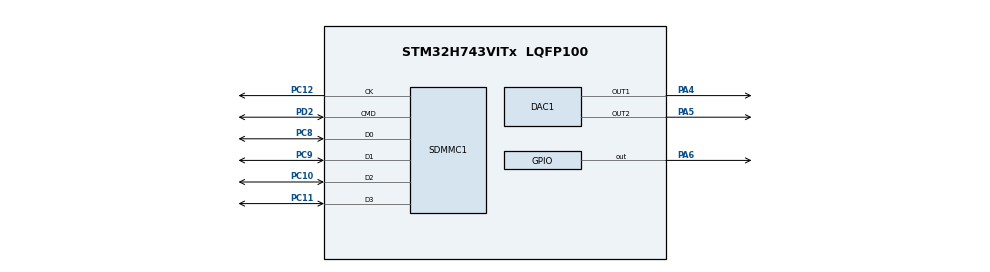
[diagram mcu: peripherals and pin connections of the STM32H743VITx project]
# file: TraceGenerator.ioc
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DAC1.DAC_Channel-DAC_OUT2=DAC_CHANNEL_2
Mcu.Family=STM32H7
Mcu.Name=STM32H743VITx
Mcu.Package=LQFP100
NVIC.PriorityGroup=NVIC_PRIORITYGROUP_4
PA13\ (JTMS/SWDIO).Mode=Serial_Wire
PA13\ (JTMS/SWDIO).Signal=DEBUG_JTMS-SWDIO
PA14\ (JTCK/SWCLK).Mode=Serial_Wire
PA14\ (JTCK/SWCLK).Signal=DEBUG_JTCK-SWCLK
PA4.Signal=COMP_DAC11_group
PA5.Signal=COMP_DAC12_group
PA6.Signal=GPIO_Output
PC10.Mode=SD_4_bits_Wide_bus
PC10.Signal=SDMMC1_D2
PC11.Mode=SD_4_bits_Wide_bus
PC11.Signal=SDMMC1_D3
PC12.Mode=SD_4_bits_Wide_bus
PC12.Signal=SDMMC1_CK
PC8.Mode=SD_4_bits_Wide_bus
PC8.Signal=SDMMC1_D0
PC9.Mode=SD_4_bits_Wide_bus
PC9.Signal=SDMMC1_D1
PD2.Mode=SD_4_bits_Wide_bus
PD2.Signal=SDMMC1_CMD
ProjectManager.HeapSize=0x200
ProjectManager.StackSize=0x400
ProjectManager.TargetToolchain=STM32CubeIDE
RCC.ADCFreq_Value=129000000
RCC.APB1Freq_Value=95600000
RCC.APB2Freq_Value=95600000
RCC.APB3Freq_Value=95600000
RCC.APB4Freq_Value=95600000
RCC.CortexFreq_Value=95600000
RCC.DIVN1=478
RCC.DIVP1=10
RCC.HCLKFreq_Value=95600000
RCC.SYSCLKFreq_VALUE=95600000
RCC.SYSCLKSource=RCC_SYSCLKSOURCE_PLLCLK
RCC.USBFreq_Value=478000000
SH.COMP_DAC11_group.0=DAC1_OUT1,DAC_OUT1
SH.COMP_DAC12_group.0=DAC1_OUT2,DAC_OUT2
VP_FATFS_VS_SDIO.Mode=SDIO
board=custom

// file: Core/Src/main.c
/* USER CODE BEGIN Header */
/**
  ******************************************************************************
  * @file           : main.c
  * @brief          : Main program body
  ******************************************************************************
  * @attention
  *
  * <h2><center>&copy; Copyright (c) 2020 STMicroelectronics.
  * All rights reserved.</center></h2>
  *
  * This software component is licensed by ST under BSD 3-Clause license,
  * the "License"; You may not use this file except in compliance with the
  * License. You may obtain a copy of the License at:
  *                        opensource.org/licenses/BSD-3-Clause
  *
  ******************************************************************************
  */
/* USER CODE END Header */
#include "main.h"
#include "fatfs.h"

DAC_HandleTypeDef hdac1;

SD_HandleTypeDef hsd1;

void SystemClock_Config(void);
static void MX_GPIO_Init(void);
static void MX_DAC1_Init(void);
static void MX_SDMMC1_SD_Init(void);

int main(void)
{

  /* MCU Configuration--------------------------------------------------------*/

  /* Reset of all peripherals, Initializes the Flash interface and the Systick. */
  HAL_Init();

  /* Configure the system clock */
  SystemClock_Config();

  /* Initialize all configured peripherals */
  MX_GPIO_Init();
  MX_DAC1_Init();
  MX_SDMMC1_SD_Init();
  MX_FATFS_Init();
  /* USER CODE BEGIN 2 */
  HAL_DAC_Start(&hdac1, DAC1_CHANNEL_1);
  HAL_DAC_Start(&hdac1, DAC1_CHANNEL_2);
  double x = 0.0;
  double x1 = 0.0;
  uint16_t y[2000];
  uint16_t y_[2000];

  for(int i=0; i < 2000; i++)
  {
	  int j = i - 500;
  	  x = (j*j*0.00002 + log(j+3));
  	  x1 = exp(-fabs(j*0.01-3));
  	  y[i]= (uint16_t)((sin(pow(x*0.5, 2) + 3)+1)*3000.0*x1);
  }
  for(int i=0; i < 2000; i++)
    {
  	  int j = i - 700;
    	  x = (j*j*0.00002 + log(j+3));
    	  x1 = exp(-fabs(j*0.01-3));
    	  y_[i]= (uint16_t)((sin(pow(x*0.5, 2) + 3)+1)*2000.0*x1);
    }
  for(int i = 20; i < 50; i++) {
	  y[i] = 4000;
  }
  /* USER CODE END 2 */

  /* Infinite loop */
  /* USER CODE BEGIN WHILE */
  while (1)
  {
	  HAL_GPIO_TogglePin(GPIOA, GPIO_PIN_6);
	  for(int i =0; i<100; i++){}
	  HAL_GPIO_TogglePin(GPIOA, GPIO_PIN_6);
	  for(int i=0; i < 2000; i++)
	  {
	  	  HAL_DAC_SetValue(&hdac1, DAC1_CHANNEL_1, DAC_ALIGN_12B_R, y_[i]);
	  	  HAL_DAC_SetValue(&hdac1, DAC1_CHANNEL_2, DAC_ALIGN_12B_R, y[i]);
	  }
    /* USER CODE END WHILE */

  }
}

void SystemClock_Config(void)
{
  RCC_OscInitTypeDef RCC_OscInitStruct = {0};
  RCC_ClkInitTypeDef RCC_ClkInitStruct = {0};
  RCC_PeriphCLKInitTypeDef PeriphClkInitStruct = {0};

  /** Supply configuration update enable
  */
  HAL_PWREx_ConfigSupply(PWR_LDO_SUPPLY);
  /** Configure the main internal regulator output voltage
  */
  __HAL_PWR_VOLTAGESCALING_CONFIG(PWR_REGULATOR_VOLTAGE_SCALE3);

  while(!__HAL_PWR_GET_FLAG(PWR_FLAG_VOSRDY)) {}
  /** Initializes the RCC Oscillators according to the specified parameters
  * in the RCC_OscInitTypeDef structure.
  */
  RCC_OscInitStruct.OscillatorType = RCC_OSCILLATORTYPE_HSI;
  RCC_OscInitStruct.HSIState = RCC_HSI_DIV1;
  RCC_OscInitStruct.HSICalibrationValue = RCC_HSICALIBRATION_DEFAULT;
  RCC_OscInitStruct.PLL.PLLState = RCC_PLL_ON;
  RCC_OscInitStruct.PLL.PLLSource = RCC_PLLSOURCE_HSI;
  RCC_OscInitStruct.PLL.PLLM = 32;
  RCC_OscInitStruct.PLL.PLLN = 129;
  RCC_OscInitStruct.PLL.PLLP = 2;
  RCC_OscInitStruct.PLL.PLLQ = 2;
  RCC_OscInitStruct.PLL.PLLR = 2;
  RCC_OscInitStruct.PLL.PLLRGE = RCC_PLL1VCIRANGE_1;
  RCC_OscInitStruct.PLL.PLLVCOSEL = RCC_PLL1VCOWIDE;
  RCC_OscInitStruct.PLL.PLLFRACN = 0;
  if (HAL_RCC_OscConfig(&RCC_OscInitStruct) != HAL_OK)
  {
    Error_Handler();
  }
  /** Initializes the CPU, AHB and APB buses clocks
  */
  RCC_ClkInitStruct.ClockType = RCC_CLOCKTYPE_HCLK|RCC_CLOCKTYPE_SYSCLK
                              |RCC_CLOCKTYPE_PCLK1|RCC_CLOCKTYPE_PCLK2
                              |RCC_CLOCKTYPE_D3PCLK1|RCC_CLOCKTYPE_D1PCLK1;
  RCC_ClkInitStruct.SYSCLKSource = RCC_SYSCLKSOURCE_HSI;
  RCC_ClkInitStruct.SYSCLKDivider = RCC_SYSCLK_DIV1;
  RCC_ClkInitStruct.AHBCLKDivider = RCC_HCLK_DIV1;
  RCC_ClkInitStruct.APB3CLKDivider = RCC_APB3_DIV1;
  RCC_ClkInitStruct.APB1CLKDivider = RCC_APB1_DIV1;
  RCC_ClkInitStruct.APB2CLKDivider = RCC_APB2_DIV1;
  RCC_ClkInitStruct.APB4CLKDivider = RCC_APB4_DIV1;

  if (HAL_RCC_ClockConfig(&RCC_ClkInitStruct, FLASH_LATENCY_0) != HAL_OK)
  {
    Error_Handler();
  }
  PeriphClkInitStruct.PeriphClockSelection = RCC_PERIPHCLK_SDMMC;
  PeriphClkInitStruct.SdmmcClockSelection = RCC_SDMMCCLKSOURCE_PLL;
  if (HAL_RCCEx_PeriphCLKConfig(&PeriphClkInitStruct) != HAL_OK)
  {
    Error_Handler();
  }
}

static void MX_DAC1_Init(void)
{

  DAC_ChannelConfTypeDef sConfig = {0};

  /** DAC Initialization
  */
  hdac1.Instance = DAC1;
  if (HAL_DAC_Init(&hdac1) != HAL_OK)
  {
    Error_Handler();
  }
  /** DAC channel OUT1 config
  */
  sConfig.DAC_SampleAndHold = DAC_SAMPLEANDHOLD_DISABLE;
  sConfig.DAC_Trigger = DAC_TRIGGER_NONE;
  sConfig.DAC_OutputBuffer = DAC_OUTPUTBUFFER_ENABLE;
  sConfig.DAC_ConnectOnChipPeripheral = DAC_CHIPCONNECT_DISABLE;
  sConfig.DAC_UserTrimming = DAC_TRIMMING_FACTORY;
  if (HAL_DAC_ConfigChannel(&hdac1, &sConfig, DAC_CHANNEL_1) != HAL_OK)
  {
    Error_Handler();
  }
  /** DAC channel OUT2 config
  */
  sConfig.DAC_ConnectOnChipPeripheral = DAC_CHIPCONNECT_DISABLE;
  if (HAL_DAC_ConfigChannel(&hdac1, &sConfig, DAC_CHANNEL_2) != HAL_OK)
  {
    Error_Handler();
  }

}

static void MX_SDMMC1_SD_Init(void)
{

  hsd1.Instance = SDMMC1;
  hsd1.Init.ClockEdge = SDMMC_CLOCK_EDGE_RISING;
  hsd1.Init.ClockPowerSave = SDMMC_CLOCK_POWER_SAVE_DISABLE;
  hsd1.Init.BusWide = SDMMC_BUS_WIDE_4B;
  hsd1.Init.HardwareFlowControl = SDMMC_HARDWARE_FLOW_CONTROL_DISABLE;
  hsd1.Init.ClockDiv = 0;
  hsd1.Init.TranceiverPresent = SDMMC_TRANSCEIVER_NOT_PRESENT;

}

static void MX_GPIO_Init(void)
{
  GPIO_InitTypeDef GPIO_InitStruct = {0};

  /* GPIO Ports Clock Enable */
  __HAL_RCC_GPIOA_CLK_ENABLE();
  __HAL_RCC_GPIOC_CLK_ENABLE();
  __HAL_RCC_GPIOD_CLK_ENABLE();

  /*Configure GPIO pin Output Level */
  HAL_GPIO_WritePin(GPIOA, GPIO_PIN_6, GPIO_PIN_RESET);

  /*Configure GPIO pin : PA6 */
  GPIO_InitStruct.Pin = GPIO_PIN_6;
  GPIO_InitStruct.Mode = GPIO_MODE_OUTPUT_PP;
  GPIO_InitStruct.Pull = GPIO_NOPULL;
  GPIO_InitStruct.Speed = GPIO_SPEED_FREQ_LOW;
  HAL_GPIO_Init(GPIOA, &GPIO_InitStruct);

}

void Error_Handler(void)
{
}

/************************ (C) COPYRIGHT STMicroelectronics *****END OF FILE****/
